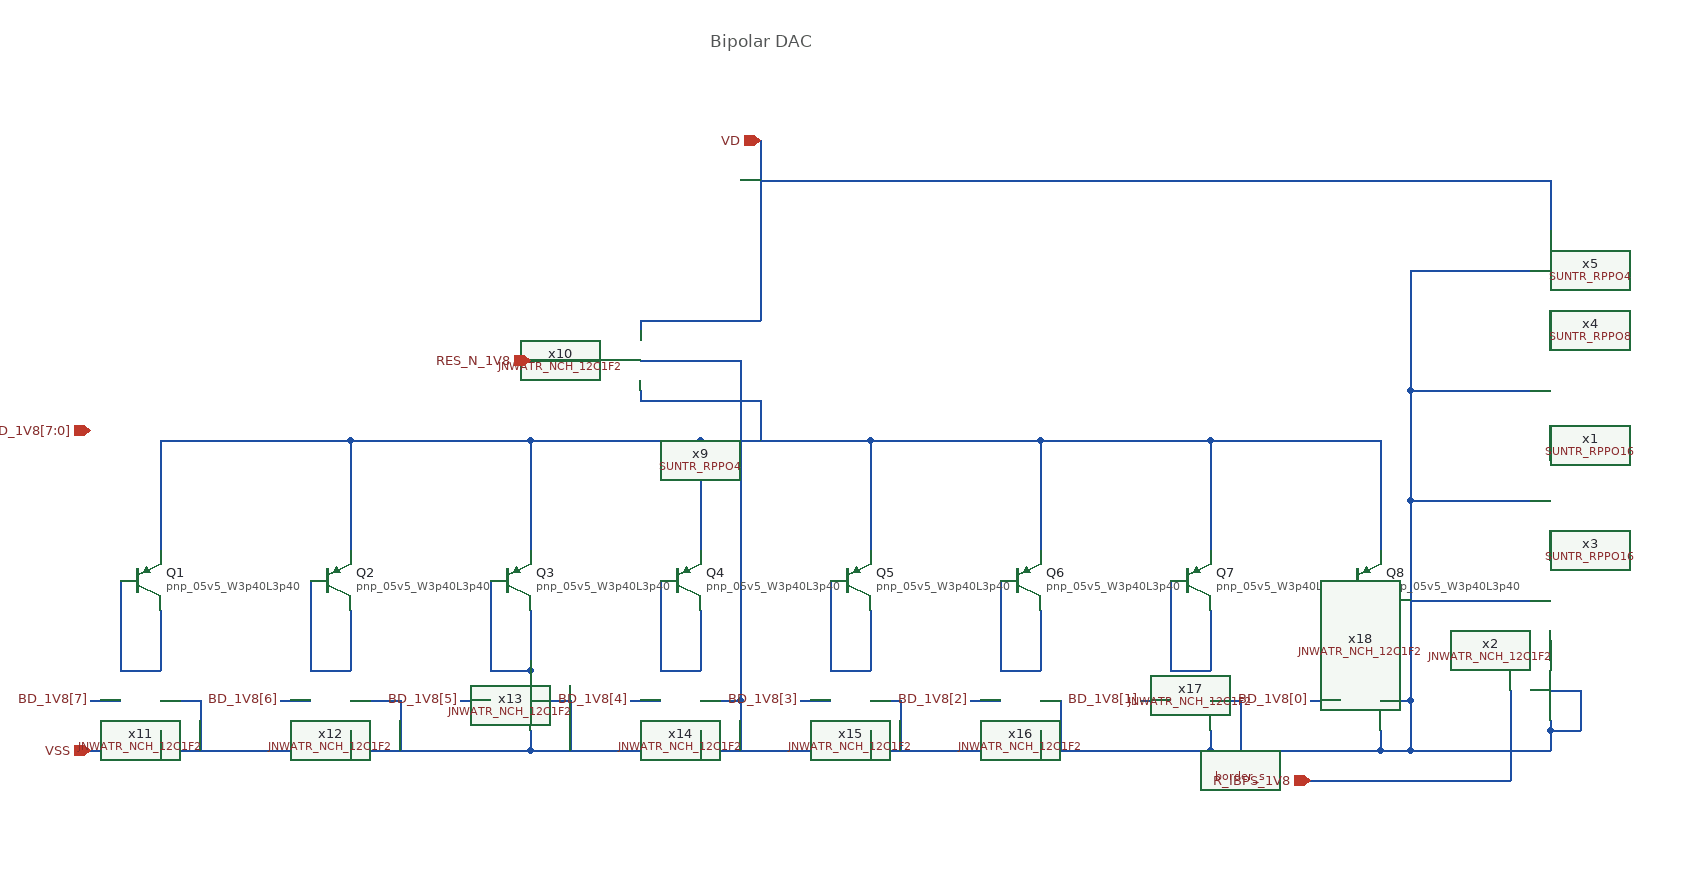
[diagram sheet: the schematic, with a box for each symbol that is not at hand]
v {xschem version=3.4.5 file_version=1.2
}
G {}
K {}
V {}
S {}
E {}
T {Bipolar DAC} 770 -940 0 0 0.5 0.5 {}
N 220 -360 220 -300 {
lab=#net1}
N 180 -390 180 -300 {
lab=#net1}
N 180 -220 220 -220 {
lab=VSS}
N 220 -220 410 -220 {
lab=VSS}
N 410 -360 410 -300 {
lab=#net2}
N 410 -220 590 -220 {
lab=VSS}
N 590 -360 590 -300 {
lab=#net3}
N 590 -220 760 -220 {
lab=VSS}
N 760 -360 760 -300 {
lab=#net4}
N 720 -390 720 -300 {
lab=#net4}
N 550 -390 550 -300 {
lab=#net3}
N 370 -390 370 -300 {
lab=#net2}
N 760 -220 930 -220 {
lab=VSS}
N 930 -360 930 -300 {
lab=#net5}
N 890 -390 890 -300 {
lab=#net5}
N 930 -220 1100 -220 {
lab=VSS}
N 1100 -360 1100 -300 {
lab=#net6}
N 1060 -390 1060 -300 {
lab=#net6}
N 1100 -220 1270 -220 {
lab=VSS}
N 1270 -360 1270 -300 {
lab=#net7}
N 1230 -390 1230 -300 {
lab=#net7}
N 1270 -220 1440 -220 {
lab=VSS}
N 1440 -360 1440 -300 {
lab=#net8}
N 1400 -390 1400 -300 {
lab=#net8}
N 1440 -440 1440 -420 {
lab=#net9}
N 1270 -440 1270 -420 {
lab=#net9}
N 1100 -440 1100 -420 {
lab=#net9}
N 930 -440 930 -420 {
lab=#net9}
N 760 -440 760 -420 {
lab=#net9}
N 590 -440 590 -420 {
lab=#net9}
N 410 -440 410 -420 {
lab=#net9}
N 220 -440 220 -420 {
lab=#net9}
N 1440 -220 1470 -220 {
lab=VSS}
N 220 -530 220 -500 {
lab=#net9}
N 220 -530 410 -530 {
lab=#net9}
N 410 -530 410 -500 {
lab=#net9}
N 410 -530 590 -530 {
lab=#net9}
N 590 -530 590 -510 {
lab=#net9}
N 760 -530 760 -500 {
lab=#net9}
N 590 -530 760 -530 {
lab=#net9}
N 930 -530 930 -500 {
lab=#net9}
N 760 -530 930 -530 {
lab=#net9}
N 1100 -530 1100 -500 {
lab=#net9}
N 930 -530 1100 -530 {
lab=#net9}
N 1270 -530 1270 -500 {
lab=#net9}
N 1100 -530 1270 -530 {
lab=#net9}
N 1440 -530 1440 -500 {
lab=#net9}
N 1270 -530 1440 -530 {
lab=#net9}
N 150 -220 180 -220 {
lab=VSS}
N 820 -570 820 -530 {
lab=#net9}
N 820 -830 820 -780 {
lab=VD}
N 700 -650 700 -640 {
lab=VD}
N 700 -650 820 -650 {
lab=VD}
N 700 -580 700 -570 {
lab=#net9}
N 700 -570 820 -570 {
lab=#net9}
N 700 -610 800 -610 {
lab=VSS}
N 580 -610 660 -610 {
lab=RES_N_1V8}
N 180 -300 220 -300 {
lab=#net1}
N 370 -300 410 -300 {
lab=#net2}
N 550 -300 590 -300 {
lab=#net3}
N 720 -300 760 -300 {
lab=#net4}
N 890 -300 930 -300 {
lab=#net5}
N 1060 -300 1100 -300 {
lab=#net6}
N 1230 -300 1270 -300 {
lab=#net7}
N 1400 -300 1440 -300 {
lab=#net8}
N 220 -270 260 -270 {
lab=VSS}
N 410 -270 460 -270 {
lab=VSS}
N 590 -270 630 -270 {
lab=VSS}
N 760 -270 800 -270 {
lab=VSS}
N 930 -270 960 -270 {
lab=VSS}
N 1100 -270 1120 -270 {
lab=VSS}
N 1270 -270 1300 -270 {
lab=VSS}
N 1440 -270 1470 -270 {
lab=VSS}
N 590 -310 590 -300 {
lab=#net3}
N 150 -270 180 -270 {
lab=BD_1V8[7]}
N 340 -270 370 -270 {
lab=BD_1V8[6]}
N 520 -270 550 -270 {
lab=BD_1V8[5]}
N 690 -270 720 -270 {
lab=BD_1V8[4]}
N 860 -270 890 -270 {
lab=BD_1V8[3]}
N 1030 -270 1060 -270 {
lab=BD_1V8[2]}
N 1200 -270 1230 -270 {
lab=BD_1V8[1]}
N 1370 -270 1400 -270 {
lab=BD_1V8[0]}
N 220 -500 220 -440 {
lab=#net9}
N 410 -500 410 -440 {
lab=#net9}
N 590 -510 590 -440 {
lab=#net9}
N 760 -500 760 -440 {
lab=#net9}
N 930 -500 930 -440 {
lab=#net9}
N 1100 -500 1100 -440 {
lab=#net9}
N 1270 -500 1270 -440 {
lab=#net9}
N 1440 -500 1440 -440 {
lab=#net9}
N 800 -610 800 -270 {
lab=VSS}
N 800 -270 800 -220 {
lab=VSS}
N 260 -270 260 -220 {
lab=VSS}
N 220 -240 220 -220 {
lab=VSS}
N 410 -240 410 -220 {
lab=VSS}
N 460 -270 460 -220 {
lab=VSS}
N 590 -240 590 -220 {
lab=VSS}
N 630 -270 630 -220 {
lab=VSS}
N 760 -240 760 -220 {
lab=VSS}
N 930 -240 930 -220 {
lab=VSS}
N 1100 -240 1100 -220 {
lab=VSS}
N 1270 -240 1270 -220 {
lab=VSS}
N 1440 -240 1440 -220 {
lab=VSS}
N 1470 -270 1470 -220 {
lab=VSS}
N 1300 -270 1300 -220 {
lab=VSS}
N 1120 -270 1120 -220 {
lab=VSS}
N 960 -270 960 -220 {
lab=VSS}
N 820 -790 1610 -790 {
lab=VD}
N 1470 -470 1590 -470 {
lab=VSS}
N 1470 -470 1470 -270 {
lab=VSS}
N 1610 -280 1640 -280 {
lab=VSS}
N 1640 -280 1640 -240 {
lab=VSS}
N 1610 -240 1640 -240 {
lab=VSS}
N 1610 -250 1610 -240 {
lab=VSS}
N 1610 -240 1610 -220 {
lab=VSS}
N 1470 -220 1610 -220 {
lab=VSS}
N 1610 -430 1610 -410 {
lab=#net10}
N 1470 -370 1590 -370 {
lab=VSS}
N 1610 -330 1610 -310 {
lab=#net11}
N 1370 -190 1570 -190 {
lab=R_IBPS_1V8}
N 1570 -280 1570 -190 {
lab=R_IBPS_1V8}
N 1610 -540 1610 -510 {
lab=#net12}
N 1610 -660 1610 -620 {
lab=#net13}
N 1470 -580 1590 -580 {
lab=VSS}
N 1470 -580 1470 -470 {
lab=VSS}
N 820 -780 820 -650 {
lab=VD}
N 1470 -700 1590 -700 {
lab=VSS}
N 1470 -700 1470 -580 {
lab=VSS}
N 1610 -790 1610 -740 {
lab=VD}
C {sky130_fd_pr/pnp_05v5.sym} 200 -390 0 0 {name=Q1
model=pnp_05v5_W3p40L3p40
spiceprefix=X
}
C {sky130_fd_pr/pnp_05v5.sym} 390 -390 0 0 {name=Q2
model=pnp_05v5_W3p40L3p40
spiceprefix=X
}
C {sky130_fd_pr/pnp_05v5.sym} 570 -390 0 0 {name=Q3
model=pnp_05v5_W3p40L3p40
spiceprefix=X
}
C {sky130_fd_pr/pnp_05v5.sym} 740 -390 0 0 {name=Q4
model=pnp_05v5_W3p40L3p40
spiceprefix=X
}
C {sky130_fd_pr/pnp_05v5.sym} 910 -390 0 0 {name=Q5
model=pnp_05v5_W3p40L3p40
spiceprefix=X
}
C {sky130_fd_pr/pnp_05v5.sym} 1080 -390 0 0 {name=Q6
model=pnp_05v5_W3p40L3p40
spiceprefix=X
}
C {sky130_fd_pr/pnp_05v5.sym} 1250 -390 0 0 {name=Q7
model=pnp_05v5_W3p40L3p40
spiceprefix=X
}
C {sky130_fd_pr/pnp_05v5.sym} 1420 -390 0 0 {name=Q8
model=pnp_05v5_W3p40L3p40
spiceprefix=X
}
C {devices/ipin.sym} 150 -220 0 0 {name=p1 lab=VSS}
C {devices/iopin.sym} 820 -830 3 0 {name=p2 lab=VD}
C {devices/ipin.sym} 150 -540 0 0 {name=p3 lab=BD_1V8[7:0]}
C {cborder/border_s.sym} 1250 -170 0 0 {
user="Carsten Wulff"
company="Carsten Wulff Software"}
C {SUN_TR_SKY130NM/SUNTR_RPPO4.sym} 820 -650 1 0 {name=x9 }
C {JNW_ATR_SKY130NM/JNWATR_NCH_12C1F2.sym} 660 -610 0 0 {name=x10 }
C {devices/ipin.sym} 590 -610 0 0 {name=p12 lab=RES_N_1V8}
C {JNW_ATR_SKY130NM/JNWATR_NCH_12C1F2.sym} 180 -270 0 0 {name=x11 }
C {JNW_ATR_SKY130NM/JNWATR_NCH_12C1F2.sym} 370 -270 0 0 {name=x12 }
C {JNW_ATR_SKY130NM/JNWATR_NCH_12C1F2.sym} 550 -270 0 0 {name=x13 }
C {JNW_ATR_SKY130NM/JNWATR_NCH_12C1F2.sym} 720 -270 0 0 {name=x14 }
C {JNW_ATR_SKY130NM/JNWATR_NCH_12C1F2.sym} 890 -270 0 0 {name=x15 }
C {JNW_ATR_SKY130NM/JNWATR_NCH_12C1F2.sym} 1060 -270 0 0 {name=x16 }
C {JNW_ATR_SKY130NM/JNWATR_NCH_12C1F2.sym} 1230 -270 0 0 {name=x17 }
C {JNW_ATR_SKY130NM/JNWATR_NCH_12C1F2.sym} 1400 -270 0 0 {name=x18 }
C {devices/lab_wire.sym} 150 -270 0 0 {name=p13 sig_type=std_logic lab=BD_1V8[7]}
C {devices/lab_wire.sym} 340 -270 0 0 {name=p14 sig_type=std_logic lab=BD_1V8[6]}
C {devices/lab_wire.sym} 520 -270 0 0 {name=p15 sig_type=std_logic lab=BD_1V8[5]}
C {devices/lab_wire.sym} 690 -270 0 0 {name=p16 sig_type=std_logic lab=BD_1V8[4]}
C {devices/lab_wire.sym} 860 -270 0 0 {name=p17 sig_type=std_logic lab=BD_1V8[3]}
C {devices/lab_wire.sym} 1030 -270 0 0 {name=p18 sig_type=std_logic lab=BD_1V8[2]}
C {devices/lab_wire.sym} 1200 -270 0 0 {name=p19 sig_type=std_logic lab=BD_1V8[1]}
C {devices/lab_wire.sym} 1370 -270 0 0 {name=p20 sig_type=std_logic lab=BD_1V8[0]}
C {SUN_TR_SKY130NM/SUNTR_RPPO16.sym} 1610 -510 1 0 {name=x1 }
C {JNW_ATR_SKY130NM/JNWATR_NCH_12C1F2.sym} 1570 -280 0 0 {name=x2 }
C {SUN_TR_SKY130NM/SUNTR_RPPO16.sym} 1610 -410 1 0 {name=x3 }
C {devices/ipin.sym} 1370 -190 0 0 {name=p4 lab=R_IBPS_1V8}
C {SUN_TR_SKY130NM/SUNTR_RPPO8.sym} 1610 -620 1 0 {name=x4 }
C {SUN_TR_SKY130NM/SUNTR_RPPO4.sym} 1610 -740 1 0 {name=x5 }
